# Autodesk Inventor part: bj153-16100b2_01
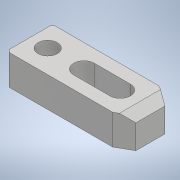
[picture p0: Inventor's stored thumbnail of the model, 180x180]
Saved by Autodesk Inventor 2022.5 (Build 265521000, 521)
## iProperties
Part Number: bj153-16100b2_01
Material: 一般
Document SubType Name: Modeling
Designer: ImaoCorp
Density: 1 g/cm^3
Appearance: 既定
Author: ImaoCorp
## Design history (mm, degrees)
feature "bj153-16100b2_01"
node "ソリッド1"
